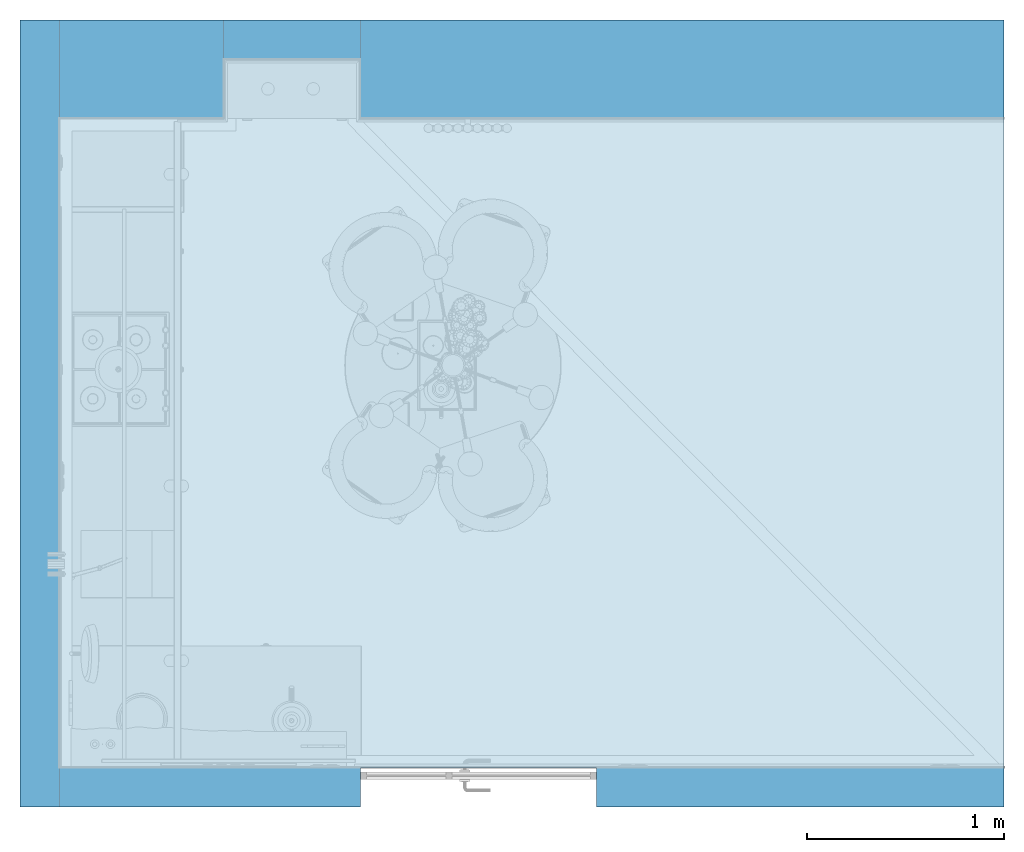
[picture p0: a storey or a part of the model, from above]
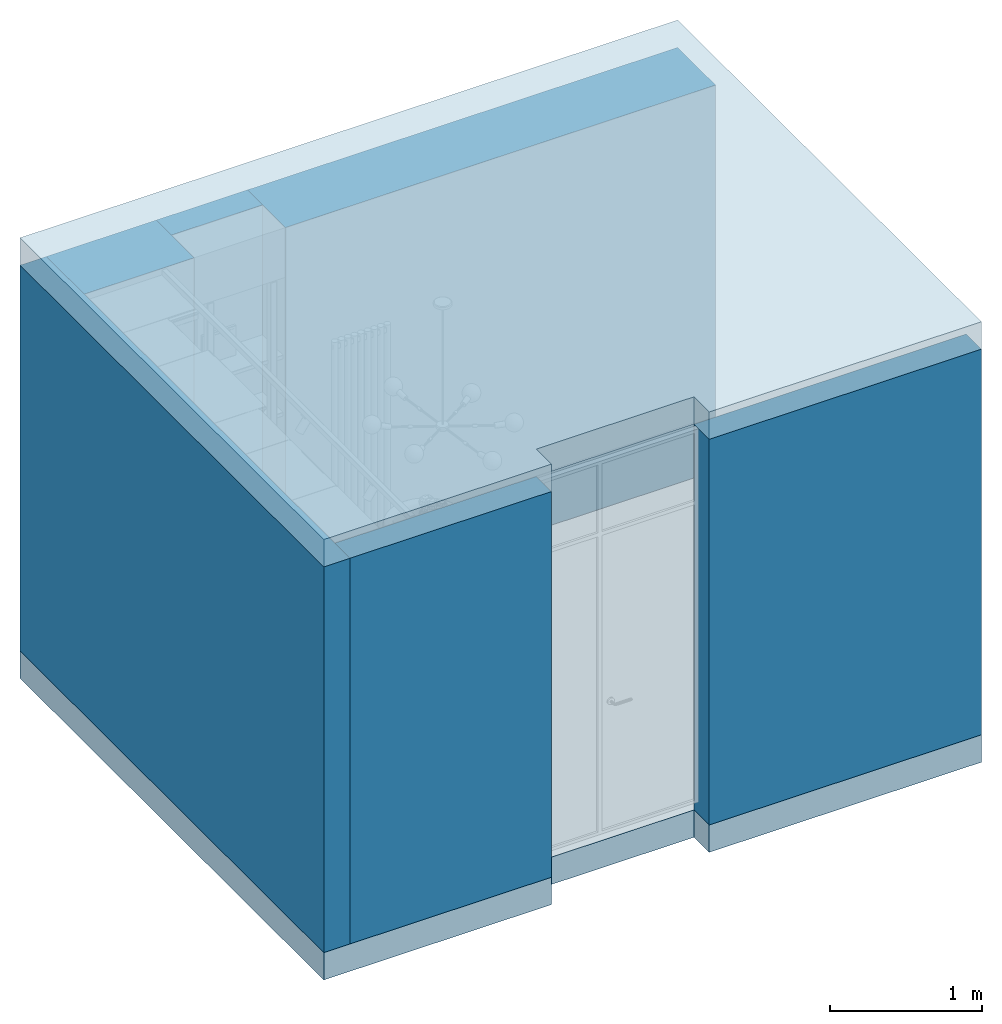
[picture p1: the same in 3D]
Properties of the parts of a building model (IFC4)

# File
Description: ViewDefinition [NotAssigned]
File name: DP-03-2026-AI_3D.ifc
Time: 2026-10-25T17:51:31
Author: Демиденко Д.
Organization: ДАНИЛ ДЕМИДЕНКО · проектирование и дизайн интерьеров
Written by: ifcw.py
Made in: dp-engine ifcw.py

# IfcProject, ДП-03-2026-АИ
Description: Дизайн-проект квартиры, —. 3D-модель по рабочей документации, ред. 1; LongName: Квартира — дизайн-проект; Phase: Рабочая документация

# IfcSite, Участок
LongName: —

# IfcBuilding, Жилой дом
LongName: Жилой дом (адрес — по договору)

# IfcBuildingStorey, Квартира ±0,000
In: Жилой дом
Description: Отметки — от чистого пола жилых помещений (±0,000); LongName: Квартира; Elevation: 0 mm

# IfcSpace, 01
In: Квартира ±0,000
Description: Кухня-столовая; LongName: Кухня-столовая; PredefinedType: INTERNAL
ДП_Параметры - Наименование: Кухня-столовая; Площадь, м²: 16; Пол: П1; Отметка пола: 0; Высота до потолка: 3000
Qto_SpaceBaseQuantities - NetFloorArea: 16 m2; Height: 3000 mm
Pset_SpaceCommon - Reference: 01; IsExternal: no; NetPlannedArea: 16 m2

# IfcAudioVisualAppliance, Телевизор 58" настенный (кронштейн)
In: Квартира ±0,000
PredefinedType: DISPLAY; Material: Металл чёрный матовый RAL 9005, Экран ТВ
ДП_Параметры - Помещение: 01; Позиция: Т1; Габарит в плане, мм: 1290×45; Отметки, мм: 1700…2445; Материалы: Металл чёрный матовый RAL 9005; Экран ТВ

# IfcCovering (13)
In: Квартира ±0,000
ДП_Параметры - Помещение: 01
Name | Description = Описание | PredefinedType | Material = Материалы | Код отделки | Стена | Привязка, мм
П1 — пол пом. 01 | Инженерная доска дуб светлый 180×1800, вдоль оси кухни | FLOORING | П1 Инженерная доска дуб светлый 180×1800, вдоль оси кухни | П1 | ДП_Параметры - Площадь, м²: 16.05; Отметка чистого пола: 0
Потолок пом. 01 |  | CEILING | Потолок ГКЛ, окраска | Пт1 | ДП_Параметры - Площадь, м²: 16.05; Отметка: 3000; Примечание: ГКЛ примыкает к встроенной мебели до потолка и крепится к ней
С1 — пом. 01, стена А | Декоративная штукатурка, светло-серая с серебристыми разводами (окраска-эффект) | CLADDING | С1 Декоративная штукатурка | С1 | А | 0…3300 от левого края; отм. 0…3000
С1 — пом. 01, стена А | Декоративная штукатурка, светло-серая с серебристыми разводами (окраска-эффект) | CLADDING | С1 Декоративная штукатурка | С1 | А | 3300…4800 от левого края; отм. 910…3000
С2 — пом. 01, стена Б | Фартук: плитка мраморная мозаика «звезда-крест» 250×250 (Nero Marquina, серый, белый) | CLADDING | С2 Плитка фартука «звезда-крест» 250×250 | С2 | Б | 0…2850 от левого края; отм. 910…1680
С1 — пом. 01, стена Б | Декоративная штукатурка, светло-серая с серебристыми разводами (окраска-эффект) | CLADDING | С1 Декоративная штукатурка | С1 | Б | 0…3300 от левого края; отм. 2950…3000
С1 — пом. 01, стена В | Декоративная штукатурка, светло-серая с серебристыми разводами (окраска-эффект) | CLADDING | С1 Декоративная штукатурка | С1 | В | 0…835 от левого края; отм. 0…3000
С1 — пом. 01, стена Г | Декоративная штукатурка, светло-серая с серебристыми разводами (окраска-эффект) | CLADDING | С1 Декоративная штукатурка | С1 | Г | 0…300 от левого края; отм. 0…3000
С1 — пом. 01, стена Д | Декоративная штукатурка, светло-серая с серебристыми разводами (окраска-эффект) | CLADDING | С1 Декоративная штукатурка | С1 | Д | 0…695 от левого края; отм. 0…3000
С1 — пом. 01, стена Е | Декоративная штукатурка, светло-серая с серебристыми разводами (окраска-эффект) | CLADDING | С1 Декоративная штукатурка | С1 | Е | 0…300 от левого края; отм. 0…3000
С1 — пом. 01, стена Ж | Декоративная штукатурка, светло-серая с серебристыми разводами (окраска-эффект) | CLADDING | С1 Декоративная штукатурка | С1 | Ж | 0…3270 от левого края; отм. 0…3000
Плинтус МДФ h=100 — пом. 01 | Плинтус МДФ белый h=80 | SKIRTINGBOARD | С1 Декоративная штукатурка | ДП_Параметры - Высота, мм: 100; Длина, м: 8.1
Галтель потолочная 60 — пом. 01 |  | MOLDING | Потолок ГКЛ, окраска | ДП_Параметры - Профиль: полиуретан 60×60, окраска в цвет потолка

# IfcCovering: Стяжка / основание пола, Основание пола пом. 01
In: Квартира ±0,000
PredefinedType: USERDEFINED; Material: Сухая стяжка / основание пола
ДП_Параметры - Помещение: 01; Толщина, мм: 85; Материалы: Сухая стяжка / основание пола

# IfcDistributionSystem (3)
Name | LongName | PredefinedType
В1 Водопровод холодный | В1 Водопровод холодный | DOMESTICCOLDWATER
Т3 Водопровод горячий | Т3 Водопровод горячий | DOMESTICHOTWATER
К1 Канализация | К1 Канализация | SEWAGE

# IfcDoor, Перегородка стеклянная с распашной дверью, стекло матовое, профиль чёрный
In: Квартира ±0,000
PredefinedType: DOOR; Material: Алюминий чёрный матовый (профиль перегородки), Стекло матовое (сатинато), Хром (ручка двери)
ДП_Параметры - Помещение: 01; Проём, мм: 1200×3000; Полотно, мм: 750×2400; Материалы: Алюминий чёрный матовый (профиль перегородки); Стекло матовое (сатинато); Хром (ручка двери)

# IfcFurniture (7)
In: Квартира ±0,000
ДП_Параметры - Помещение: 01
Name | PredefinedType | Material | Позиция | Габарит в плане, мм | Отметки, мм | Материалы
Стол обеденный круглый Ø1100, точёная опора (орех, латунь, шар-керамика) | TABLE | Шпон ореха, Камень светлый (столешница стола), Латунь полированная (каркасы, ручки, светильники), Керамика глазурованная серая (шар опоры стола) | 2 | 1100×1100 | 0…760 | столешница камень светлый на орехе; опора орех, латунь, керамика глазурь
4 x Стул-полукресло: латунный каркас, велюр серый | CHAIR | Латунь полированная (каркасы, ручки, светильники), Велюр серый (стулья) | 3 | 460×460 | 0…780 | каркас — латунь полированная, сиденье и спинка — велюр серый
Полка — массив ореха с живым краем 1400×230×45, латунные кронштейны | SHELF | Шпон ореха, Латунь полированная (каркасы, ручки, светильники), Эмаль белая (кастрюля, банки) | 4 | 1400×230 | 1385…1430 | Шпон ореха; Латунь полированная (каркасы, ручки, светильники); Эмаль белая (кастрюля, банки)
Ниша со стеллажом: 3 полки, стойки орех 50×50, подсветка | SHELF | С1 Декоративная штукатурка, Белый матовый (техника, радиаторы), Шпон ореха, Латунь полированная (каркасы, ручки, светильники), Картина / фото, чёрная графика, Керамика бирюзовая (декор ниши), Фарфор белый с кобальтовым узором | 5 | 695×300 | 0…2600 | С1 Декоративная штукатурка; Белый матовый (техника, радиаторы); Шпон ореха; Латунь полированная (каркасы, ручки, светильники); Картина / фото, чёрная графика; Керамика бирюзовая (декор ниши); Фарфор белый с кобальтовым узором | ДП_Параметры - Состав: ниша 695×300×2600, полки ЛДСП белая 30 мм, стойки массив ореха 50×50, подсветка

# IfcFurniture: Декор (2)
In: Квартира ±0,000
PredefinedType: USERDEFINED
ДП_Параметры - Помещение: 01; Назначение: декор по визуализации
Name | Material | Материалы
Декор кухни: чайник, банка, доска, сковорода, кастрюля | Латунь полированная (каркасы, ручки, светильники), Сталь эмаль графит-металлик (чайник), Эмаль белая (кастрюля, банки), Медь полированная (сковорода, декор), Шпон ореха, Нержавеющая сталь | Латунь полированная (каркасы, ручки, светильники); Сталь эмаль графит-металлик (чайник); Эмаль белая (кастрюля, банки); Медь полированная (сковорода, декор); Шпон ореха; Нержавеющая сталь
Сервировка стола: поднос, чайник, чашки, тарелки, ваза с гортензиями | Латунь полированная (каркасы, ручки, светильники), Фарфор белый с кобальтовым узором, Выпечка (декор стола), Эмаль белая (кастрюля, банки), Стекло дымчатое (ваза), Гортензия кремовая (декор), Зелень (декор) | Латунь полированная (каркасы, ручки, светильники); Фарфор белый с кобальтовым узором; Выпечка (декор стола); Эмаль белая (кастрюля, банки); Стекло дымчатое (ваза); Гортензия кремовая (декор); Зелень (декор)

# IfcFurniture: Кухня — верхние шкафы, Кухня — верхние шкафы до карниза (2 витрины с переплётом, шкаф-вытяжка)
In: Квартира ±0,000
PredefinedType: USERDEFINED; Material: Фасады МДФ «шейкер», эмаль матовая NCS S 4040-R80B, Латунь полированная (каркасы, ручки, светильники), Эмаль белая (кастрюля, банки), Белый матовый (техника, радиаторы), Светодиодная лента (свечение), Фарфор белый с кобальтовым узором, Стекло прозрачное, Нержавеющая сталь, Металл чёрный матовый RAL 9005
ДП_Параметры - Помещение: 01; Позиция: 1; Габарит в плане, мм: 350×2850; Отметки, мм: 1680…2950; Фасады: шейкер, эмаль NCS S 4040-R80B; витрины — стекло с переплётом «кольца»; Подсветка: светодиодная под шкафами + в витринах; Материалы: Фасады МДФ «шейкер», эмаль матовая NCS S 4040-R80B; Латунь полированная (каркасы, ручки, светильники); Эмаль белая (кастрюля, банки); Белый матовый (техника, радиаторы); Светодиодная лента (свечение); Фарфор белый с кобальтовым узором; Стекло прозрачное; Нержавеющая сталь; Металл чёрный матовый RAL 9005

# IfcFurniture: Кухня — колонна, Кухня — колонна 450 с встроенным холодильником
In: Квартира ±0,000
PredefinedType: USERDEFINED; Material: Фасады МДФ «шейкер», эмаль матовая NCS S 4040-R80B, Латунь полированная (каркасы, ручки, светильники)
ДП_Параметры - Помещение: 01; Позиция: 1; Габарит в плане, мм: 600×450; Отметки, мм: 0…2950; Встроенная техника: холодильник с морозильной камерой (по кадру — две двери; уточнить); Материалы: Фасады МДФ «шейкер», эмаль матовая NCS S 4040-R80B; Латунь полированная (каркасы, ручки, светильники)

# IfcFurniture: Кухня — нижние модули (2)
In: Квартира ±0,000
PredefinedType: USERDEFINED
ДП_Параметры - Помещение: 01; Позиция: 1; Отметки, мм: 0…910
Name | Material | Габарит в плане, мм | Материалы
Кухня — нижние модули у левой стены 1500×600 (торец к столовой) | Фасады МДФ «шейкер», эмаль матовая NCS S 4040-R80B, Латунь полированная (каркасы, ручки, светильники), Шпон ореха | 1500×600 | Фасады МДФ «шейкер», эмаль матовая NCS S 4040-R80B; Латунь полированная (каркасы, ручки, светильники); Шпон ореха | ДП_Параметры - Фасады: МДФ «шейкер», эмаль матовая NCS S 4040-R80B; ручки-ракушки и кнопки — латунь; Столешница: Массив ореха 40 мм, масло
Кухня — нижние модули у стены фартука 2250×600 | Фасады МДФ «шейкер», эмаль матовая NCS S 4040-R80B, Латунь полированная (каркасы, ручки, светильники), Шпон ореха, Нержавеющая сталь, Стекло чёрное (техника), Чугун (решётки варочной панели), Латунь матовая (фурнитура, декор светильников) | 600×2250 | Фасады МДФ «шейкер», эмаль матовая NCS S 4040-R80B; Латунь полированная (каркасы, ручки, светильники); Шпон ореха; Нержавеющая сталь; Стекло чёрное (техника); Чугун (решётки варочной панели); Латунь матовая (фурнитура, декор светильников) | ДП_Параметры - Мойка: подстольная сталь 340×360, смеситель латунь; Варочная панель: газовая 4 конфорки, чёрное стекло (по кадру — уточнить)

# IfcLightFixture (9)
In: Квартира ±0,000
ДП_Параметры - Помещение: 01
Name | PredefinedType | Material | Группа | Тип | Примечание | Материалы | Отметка, мм
Магнитный трек накладной черный + 3 спота латунь (01а) | DIRECTIONSOURCE | Металл чёрный матовый RAL 9005, Латунь полированная (каркасы, ручки, светильники), Светодиодная лента (свечение) | 1А | track | магнитный трек накладной, 3 спота латунь | Металл чёрный матовый RAL 9005; Латунь полированная (каркасы, ручки, светильники); Светодиодная лента (свечение)
Люстра «молекула» 6 ламп G125, латунь (01б) | POINTSOURCE | Латунь полированная (каркасы, ручки, светильники), Опаловое стекло (плафоны) | 1Б | pend | люстра «молекула» 6 ламп G125, латунь | Латунь полированная (каркасы, ручки, светильники); Опаловое стекло (плафоны) | 2000
Светодиодная лента (1В) | DIRECTIONSOURCE | Нержавеющая сталь, Светодиодная лента (свечение) | 1В | led | подсветка рабочей зоны под верхними шкафами | Нержавеющая сталь; Светодиодная лента (свечение) | 1680 | ДП_Параметры - Длина, м: 2.81
2 x Светильник мебельный накладной (01г) | POINTSOURCE | Латунь полированная (каркасы, ручки, светильники), Светодиодная лента (свечение) | 1Г | spot | светильник мебельный в нише | Латунь полированная (каркасы, ручки, светильники); Светодиодная лента (свечение) | 2600
2 x Светильник мебельный накладной (01г) | POINTSOURCE | Латунь полированная (каркасы, ручки, светильники), Светодиодная лента (свечение) | 1Г | spot | светильник мебельный в нише | Латунь полированная (каркасы, ручки, светильники); Светодиодная лента (свечение) | 1930
2 x Светильник мебельный накладной (01г) | POINTSOURCE | Латунь полированная (каркасы, ручки, светильники), Светодиодная лента (свечение) | 1Г | spot | светильник мебельный в нише | Латунь полированная (каркасы, ручки, светильники); Светодиодная лента (свечение) | 1470

# IfcOutlet (6)
In: Квартира ±0,000
Material: ЭУИ белые матовые (по кадру), Металл чёрный матовый RAL 9005
ДП_Параметры - Помещение: 01; Материалы: ЭУИ белые матовые (по кадру); Металл чёрный матовый RAL 9005
Name | PredefinedType | Высота (низ рамки), мм | Примечание
Розетка двойная +1100 | POWEROUTLET | 1100 | над столешницей
Розетка двойная +1100 | POWEROUTLET | 1100 | над столешницей, чайник
Блок 2Р+TV+RJ45 +2000 | DATAOUTLET | 2000 | за ТВ: 2Р + TV + RJ45
Силовой вывод 32 А +600 | POWEROUTLET | 600 | варочная панель / розжиг
Розетка +2100 | POWEROUTLET | 2100 | холодильник (в колонне)
Розетка двойная +300 | POWEROUTLET | 300

# IfcPipeFitting (3)
In: Квартира ±0,000
PredefinedType: EXIT
ДП_Параметры - Помещение: 01; Прибор: С1 мойка
Name | Material | Отметка, мм | Материалы | Group
Вывод ХВС (водорозетка) — С1 мойка | Латунь матовая (фурнитура, декор светильников), PEX в гофре — ХВС (синий) | 500 | Латунь матовая (фурнитура, декор светильников); PEX в гофре — ХВС (синий) | В1 Водопровод холодный
Вывод ГВС (водорозетка) — С1 мойка | Латунь матовая (фурнитура, декор светильников), PEX в гофре — ГВС (красный) | 500 | Латунь матовая (фурнитура, декор светильников); PEX в гофре — ГВС (красный) | Т3 Водопровод горячий
Вывод канализации Ø50 — С1 мойка | Полипропилен серый (канализация) | 400 | Полипропилен серый (канализация) | К1 Канализация

# IfcSlab (2)
In: Квартира ±0,000
PredefinedType: FLOOR; Material: Железобетон (плиты, существующие)
ДП_Параметры - Статус: существующая; Материалы: Железобетон (плиты, существующие)
Name
Плита перекрытия (под квартирой)
Плита перекрытия (над квартирой) | ДП_Параметры - Скрыть для вида сверху: да

# IfcSpaceHeater, Радиатор трубчатый вертикальный 1850×450, графит (уточнить по месту)
In: Квартира ±0,000
PredefinedType: RADIATOR; Material: Сталь окрашенная, графит (радиатор)
ДП_Параметры - Помещение: 01; Габарит в плане, мм: 450×100; Отметки, мм: 150…2000; Материалы: Сталь окрашенная, графит (радиатор)

# IfcSwitchingDevice (2)
In: Квартира ±0,000
PredefinedType: TOGGLESWITCH; Material: ЭУИ белые матовые (по кадру)
ДП_Параметры - Помещение: 01; Высота (низ рамки), мм: 900; Материалы: ЭУИ белые матовые (по кадру)
Name | Группы
Выключатель двухклавишный +900 | 1А, 1Б
Выключатель двухклавишный +900 | 1В, 1Г

# IfcWall (6)
In: Квартира ±0,000
PredefinedType: SOLIDWALL; Material: Штукатурка (стены, сущ.)
ДП_Параметры - Статус: существующая; Несущая: нет; Материалы: Штукатурка (стены, сущ.)
Name | Толщина, мм
4 x Стена 200 мм — перегородка (сущ.) | 200
2 x Стена 500 мм — перегородка (сущ.) | 500
